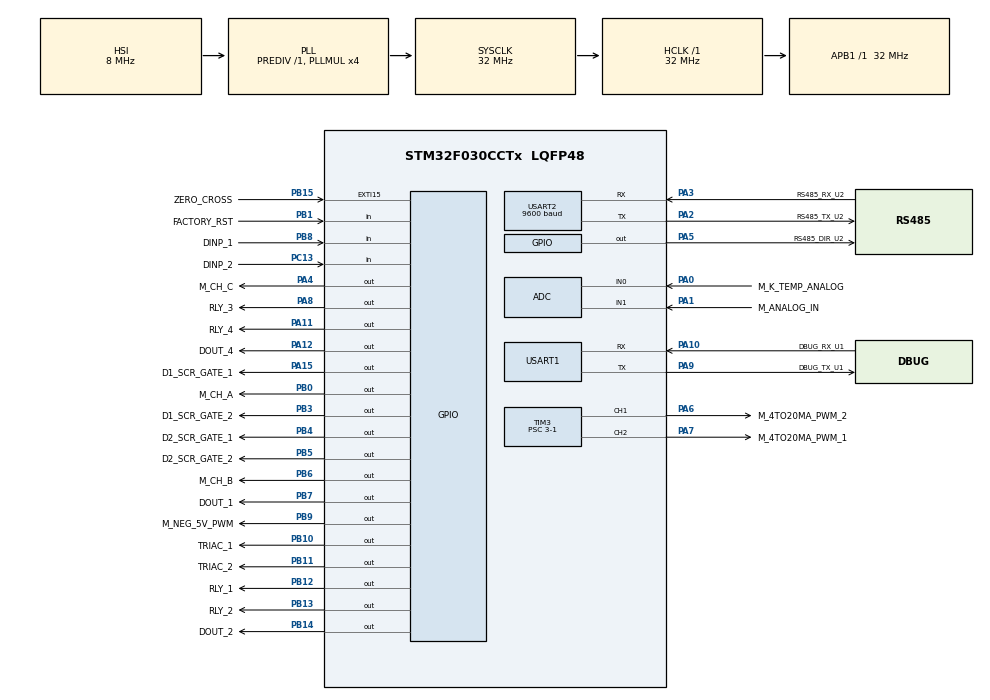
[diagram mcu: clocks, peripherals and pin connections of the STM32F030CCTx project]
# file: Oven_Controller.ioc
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ADC.ContinuousConvMode=DISABLE
ADC.DMAContinuousRequests=DISABLE
ADC.DiscontinuousConvMode=DISABLE
ADC.EOCSelection=ADC_EOC_SINGLE_CONV
ADC.SamplingTime=ADC_SAMPLETIME_71CYCLES_5
IWDG.Prescaler=IWDG_PRESCALER_64
Mcu.Family=STM32F0
Mcu.Name=STM32F030CCTx
Mcu.Package=LQFP48
NVIC.EXTI4_15_IRQn=true\:1\:0\:true\:false\:true\:true\:true
NVIC.TIM14_IRQn=true\:2\:0\:true\:false\:true\:true\:true
NVIC.TIM15_IRQn=true\:2\:0\:true\:false\:true\:true\:true
NVIC.TIM6_IRQn=true\:0\:0\:true\:false\:true\:true\:true
NVIC.TIM7_IRQn=true\:0\:0\:true\:false\:true\:true\:true
NVIC.USART1_IRQn=true\:3\:0\:true\:false\:true\:true\:true
NVIC.USART2_IRQn=true\:0\:0\:true\:false\:true\:true\:true
PA0.GPIO_Label=M_K_TEMP_ANALOG
PA0.Mode=IN0
PA0.Signal=ADC_IN0
PA1.GPIO_Label=M_ANALOG_IN
PA1.Mode=IN1
PA1.Signal=ADC_IN1
PA10.GPIO_Label=DBUG_RX_U1
PA10.Mode=Asynchronous
PA10.Signal=USART1_RX
PA11.GPIO_Label=RLY_4
PA11.GPIO_Speed=GPIO_SPEED_FREQ_HIGH
PA11.Signal=GPIO_Output
PA12.GPIO_Label=DOUT_4
PA12.GPIO_ModeDefaultOutputPP=GPIO_MODE_OUTPUT_OD
PA12.GPIO_PuPd=GPIO_NOPULL
PA12.GPIO_Speed=GPIO_SPEED_FREQ_HIGH
PA12.PinState=GPIO_PIN_SET
PA12.Signal=GPIO_Output
PA15.GPIO_Label=D1_SCR_GATE_1
PA15.Signal=GPIO_Output
PA2.GPIO_Label=RS485_TX_U2
PA2.Mode=Asynchronous
PA2.Signal=USART2_TX
PA3.GPIO_Label=RS485_RX_U2
PA3.Mode=Asynchronous
PA3.Signal=USART2_RX
PA4.GPIO_Label=M_CH_C
PA4.GPIO_Speed=GPIO_SPEED_FREQ_HIGH
PA4.Signal=GPIO_Output
PA5.GPIO_Label=RS485_DIR_U2
PA5.Signal=GPIO_Output
PA6.GPIO_Label=M_4TO20MA_PWM_2
PA6.Signal=S_TIM3_CH1
PA7.GPIO_Label=M_4TO20MA_PWM_1
PA7.Signal=S_TIM3_CH2
PA8.GPIO_Label=RLY_3
PA8.GPIO_Speed=GPIO_SPEED_FREQ_HIGH
PA8.Signal=GPIO_Output
PA9.GPIO_Label=DBUG_TX_U1
PA9.Mode=Asynchronous
PA9.Signal=USART1_TX
PB0.GPIO_Label=M_CH_A
PB0.GPIO_Speed=GPIO_SPEED_FREQ_HIGH
PB0.Signal=GPIO_Output
PB1.GPIO_Label=FACTORY_RST
PB1.Signal=GPIO_Input
PB10.GPIO_Label=TRIAC_1
PB10.Signal=GPIO_Output
PB11.GPIO_Label=TRIAC_2
PB11.Signal=GPIO_Output
PB12.GPIO_Label=RLY_1
PB12.Signal=GPIO_Output
PB13.GPIO_Label=RLY_2
PB13.Signal=GPIO_Output
PB14.GPIO_Label=DOUT_2
PB14.GPIO_ModeDefaultOutputPP=GPIO_MODE_OUTPUT_OD
PB14.GPIO_PuPd=GPIO_NOPULL
PB14.GPIO_Speed=GPIO_SPEED_FREQ_HIGH
PB14.PinState=GPIO_PIN_SET
PB14.Signal=GPIO_Output
PB15.GPIO_Label=ZERO_CROSS
PB15.GPIO_ModeDefaultEXTI=GPIO_MODE_IT_RISING
PB15.Signal=GPXTI15
PB3.GPIO_Label=D1_SCR_GATE_2
PB3.Signal=GPIO_Output
PB4.GPIO_Label=D2_SCR_GATE_1
PB4.Signal=GPIO_Output
PB5.GPIO_Label=D2_SCR_GATE_2
PB5.Signal=GPIO_Output
PB6.GPIO_FM6=SYSCFG_CFGR1_I2C_FMP_PB6
PB6.GPIO_Label=M_CH_B
PB6.GPIO_Speed=GPIO_SPEED_FREQ_HIGH
PB6.Signal=GPIO_Output
PB7.GPIO_FM7=__NULL
PB7.GPIO_Label=DOUT_1
PB7.GPIO_ModeDefaultOutputPP=GPIO_MODE_OUTPUT_OD
PB7.GPIO_PuPd=GPIO_NOPULL
PB7.GPIO_Speed=GPIO_SPEED_FREQ_HIGH
PB7.PinState=GPIO_PIN_SET
PB7.Signal=GPIO_Output
PB8.GPIO_Label=DINP_1
PB8.Signal=GPIO_Input
PB9.GPIO_FM9=SYSCFG_CFGR1_I2C_FMP_PB9
PB9.GPIO_Label=M_NEG_5V_PWM
PB9.GPIO_Speed=GPIO_SPEED_FREQ_HIGH
PB9.Signal=GPIO_Output
PC13.GPIO_Label=DINP_2
PC13.Signal=GPIO_Input
PC14OSC32_IN.GPIO_Label=DINP_3
PC14OSC32_IN.Signal=GPIO_Input
PC15OSC32_OUT.GPIO_Label=DINP_4
PC15OSC32_OUT.Signal=GPIO_Input
ProjectManager.HeapSize=0x200
ProjectManager.StackSize=0x400
ProjectManager.TargetToolchain=STM32CubeIDE
RCC.AHBFreq_Value=32000000
RCC.APB1Freq_Value=32000000
RCC.APB1TimFreq_Value=32000000
RCC.HCLKFreq_Value=32000000
RCC.PLLMUL=RCC_PLL_MUL4
RCC.SYSCLKFreq_VALUE=32000000
RCC.SYSCLKSource=RCC_SYSCLKSOURCE_PLLCLK
SH.S_TIM3_CH1.0=TIM3_CH1,PWM Generation1 CH1
SH.S_TIM3_CH2.0=TIM3_CH2,PWM Generation2 CH2
TIM14.Period=100
TIM14.Prescaler=32-1
TIM15.Period=30000
TIM15.Prescaler=32-1
TIM15.TIM_MasterOutputTrigger=TIM_TRGO_ENABLE
TIM3.Channel-PWM\ Generation1\ CH1=TIM_CHANNEL_1
TIM3.Channel-PWM\ Generation2\ CH2=TIM_CHANNEL_2
TIM3.OCPolarity_1=TIM_OCPOLARITY_HIGH
TIM3.Period=1536-1
TIM3.Prescaler=3-1
TIM3.Pulse-PWM\ Generation1\ CH1=0
TIM3.TIM_MasterOutputTrigger=TIM_TRGO_ENABLE
TIM6.Period=1563
TIM6.Prescaler=32-1
TIM7.Period=3647
TIM7.Prescaler=32-1
USART1.VirtualMode-Asynchronous=VM_ASYNC
USART2.BaudRate=9600
USART2.Parity=PARITY_EVEN
USART2.VirtualMode-Asynchronous=VM_ASYNC
USART2.WordLength=WORDLENGTH_9B
VP_IWDG_VS_IWDG.Mode=IWDG_Activate
VP_TIM14_VS_ClockSourceINT.Mode=Enable_Timer
VP_TIM15_VS_ClockSourceINT.Mode=Internal
VP_TIM3_VS_ClockSourceINT.Mode=Internal
VP_TIM6_VS_ClockSourceINT.Mode=Enable_Timer
VP_TIM7_VS_ClockSourceINT.Mode=Enable_Timer
board=custom

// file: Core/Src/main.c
/* USER CODE BEGIN Header */
/**
  ******************************************************************************
  * @file           : main.c
  * @brief          : Main program body
  ******************************************************************************
  * @attention
  *
  * Copyright (c) 2024 STMicroelectronics.
  * All rights reserved.
  *
  * This software is licensed under terms that can be found in the LICENSE file
  * in the root directory of this software component.
  * If no LICENSE file comes with this software, it is provided AS-IS.
  *
  ******************************************************************************
  */
/* USER CODE END Header */
#include "main.h"

/* USER CODE BEGIN Includes */
#include "OD_PWM.h"
#include "Test.h"
#include "debug.h"

/* USER CODE END Includes */

/* USER CODE BEGIN PM */
// extern uint16_t buf1[500], buf2[500], index, c1, c2;
/* USER CODE END PM */

ADC_HandleTypeDef hadc;

IWDG_HandleTypeDef hiwdg;

TIM_HandleTypeDef htim3;
TIM_HandleTypeDef htim6;
TIM_HandleTypeDef htim7;
TIM_HandleTypeDef htim14;
TIM_HandleTypeDef htim15;

UART_HandleTypeDef huart1;
UART_HandleTypeDef huart2;

/* USER CODE BEGIN PV */

GVar_ts gVar;

/* USER CODE END PV */

void SystemClock_Config(void);
static void MX_GPIO_Init(void);
static void MX_ADC_Init(void);
static void MX_TIM6_Init(void);
static void MX_TIM7_Init(void);
static void MX_USART1_UART_Init(void);
static void MX_USART2_UART_Init(void);
static void MX_TIM3_Init(void);
static void MX_TIM14_Init(void);
static void MX_IWDG_Init(void);
static void MX_TIM15_Init(void);
/* USER CODE BEGIN PFP */
//void DebugPrintf(const char *fmt, ...);
/* USER CODE END PFP */

int main(void)
{

  /* MCU Configuration--------------------------------------------------------*/

  /* Reset of all peripherals, Initializes the Flash interface and the Systick. */
  HAL_Init();

  /* Configure the system clock */
  SystemClock_Config();

  /* Initialize all configured peripherals */
  MX_GPIO_Init();
  MX_ADC_Init();
  MX_TIM6_Init();
  MX_TIM7_Init();
  MX_USART1_UART_Init();
  MX_USART2_UART_Init();
  MX_TIM3_Init();
  MX_TIM14_Init();
  // MX_IWDG_Init();
  MX_TIM15_Init();
  /* USER CODE BEGIN 2 */

//  ExecutionTimeCalculate();
  Test_Init();
  /* USER CODE END 2 */

  /* Infinite loop */
  /* USER CODE BEGIN WHILE */

  while (1)
  {
//	  HAL_UART_Transmit(&huart1, (uint8_t *)msg, strlen(msg), HAL_MAX_DELAY);

	  Test_Handler();

    /* USER CODE END WHILE */

  }
}

void SystemClock_Config(void)
{
  RCC_OscInitTypeDef RCC_OscInitStruct = {0};
  RCC_ClkInitTypeDef RCC_ClkInitStruct = {0};
  RCC_PeriphCLKInitTypeDef PeriphClkInit = {0};

  /** Initializes the RCC Oscillators according to the specified parameters
  * in the RCC_OscInitTypeDef structure.
  */
  RCC_OscInitStruct.OscillatorType = RCC_OSCILLATORTYPE_HSI|RCC_OSCILLATORTYPE_HSI14
                              |RCC_OSCILLATORTYPE_LSI;
  RCC_OscInitStruct.HSIState = RCC_HSI_ON;
  RCC_OscInitStruct.HSI14State = RCC_HSI14_ON;
  RCC_OscInitStruct.HSICalibrationValue = RCC_HSICALIBRATION_DEFAULT;
  RCC_OscInitStruct.HSI14CalibrationValue = 16;
  RCC_OscInitStruct.LSIState = RCC_LSI_ON;
  RCC_OscInitStruct.PLL.PLLState = RCC_PLL_ON;
  RCC_OscInitStruct.PLL.PLLSource = RCC_PLLSOURCE_HSI;
  RCC_OscInitStruct.PLL.PLLMUL = RCC_PLL_MUL4;
  RCC_OscInitStruct.PLL.PREDIV = RCC_PREDIV_DIV1;
  if (HAL_RCC_OscConfig(&RCC_OscInitStruct) != HAL_OK)
  {
    Error_Handler();
  }
  /** Initializes the CPU, AHB and APB buses clocks
  */
  RCC_ClkInitStruct.ClockType = RCC_CLOCKTYPE_HCLK|RCC_CLOCKTYPE_SYSCLK
                              |RCC_CLOCKTYPE_PCLK1;
  RCC_ClkInitStruct.SYSCLKSource = RCC_SYSCLKSOURCE_PLLCLK;
  RCC_ClkInitStruct.AHBCLKDivider = RCC_SYSCLK_DIV1;
  RCC_ClkInitStruct.APB1CLKDivider = RCC_HCLK_DIV1;

  if (HAL_RCC_ClockConfig(&RCC_ClkInitStruct, FLASH_LATENCY_1) != HAL_OK)
  {
    Error_Handler();
  }
  PeriphClkInit.PeriphClockSelection = RCC_PERIPHCLK_USART1;
  PeriphClkInit.Usart1ClockSelection = RCC_USART1CLKSOURCE_PCLK1;
  if (HAL_RCCEx_PeriphCLKConfig(&PeriphClkInit) != HAL_OK)
  {
    Error_Handler();
  }
}

static void MX_ADC_Init(void)
{

  ADC_ChannelConfTypeDef sConfig = {0};

  /** Configure the global features of the ADC (Clock, Resolution, Data Alignment and number of conversion)
  */
  hadc.Instance = ADC1;
  hadc.Init.ClockPrescaler = ADC_CLOCK_ASYNC_DIV1;
  hadc.Init.Resolution = ADC_RESOLUTION_12B;
  hadc.Init.DataAlign = ADC_DATAALIGN_RIGHT;
  hadc.Init.ScanConvMode = ADC_SCAN_DIRECTION_FORWARD;
  hadc.Init.EOCSelection = ADC_EOC_SINGLE_CONV;
  hadc.Init.LowPowerAutoWait = DISABLE;
  hadc.Init.LowPowerAutoPowerOff = DISABLE;
  hadc.Init.ContinuousConvMode = DISABLE;
  hadc.Init.DiscontinuousConvMode = DISABLE;
  hadc.Init.ExternalTrigConv = ADC_SOFTWARE_START;
  hadc.Init.ExternalTrigConvEdge = ADC_EXTERNALTRIGCONVEDGE_NONE;
  hadc.Init.DMAContinuousRequests = DISABLE;
  hadc.Init.Overrun = ADC_OVR_DATA_PRESERVED;
  if (HAL_ADC_Init(&hadc) != HAL_OK)
  {
    Error_Handler();
  }
  /** Configure for the selected ADC regular channel to be converted.
  */
  sConfig.Channel = ADC_CHANNEL_0;
  sConfig.Rank = ADC_RANK_CHANNEL_NUMBER;
  sConfig.SamplingTime = ADC_SAMPLETIME_71CYCLES_5;
  if (HAL_ADC_ConfigChannel(&hadc, &sConfig) != HAL_OK)
  {
    Error_Handler();
  }
  /** Configure for the selected ADC regular channel to be converted.
  */
  sConfig.Channel = ADC_CHANNEL_1;
  if (HAL_ADC_ConfigChannel(&hadc, &sConfig) != HAL_OK)
  {
    Error_Handler();
  }

}

static void MX_IWDG_Init(void)
{

  hiwdg.Instance = IWDG;
  hiwdg.Init.Prescaler = IWDG_PRESCALER_64;
  hiwdg.Init.Window = 4095;
  hiwdg.Init.Reload = 4095;
  if (HAL_IWDG_Init(&hiwdg) != HAL_OK)
  {
    Error_Handler();
  }

}

static void MX_TIM3_Init(void)
{

  TIM_ClockConfigTypeDef sClockSourceConfig = {0};
  TIM_MasterConfigTypeDef sMasterConfig = {0};
  TIM_OC_InitTypeDef sConfigOC = {0};

  htim3.Instance = TIM3;
  htim3.Init.Prescaler = 3-1;
  htim3.Init.CounterMode = TIM_COUNTERMODE_UP;
  htim3.Init.Period = 1536-1;
  htim3.Init.ClockDivision = TIM_CLOCKDIVISION_DIV1;
  htim3.Init.AutoReloadPreload = TIM_AUTORELOAD_PRELOAD_DISABLE;
  if (HAL_TIM_Base_Init(&htim3) != HAL_OK)
  {
    Error_Handler();
  }
  sClockSourceConfig.ClockSource = TIM_CLOCKSOURCE_INTERNAL;
  if (HAL_TIM_ConfigClockSource(&htim3, &sClockSourceConfig) != HAL_OK)
  {
    Error_Handler();
  }
  if (HAL_TIM_PWM_Init(&htim3) != HAL_OK)
  {
    Error_Handler();
  }
  sMasterConfig.MasterOutputTrigger = TIM_TRGO_ENABLE;
  sMasterConfig.MasterSlaveMode = TIM_MASTERSLAVEMODE_DISABLE;
  if (HAL_TIMEx_MasterConfigSynchronization(&htim3, &sMasterConfig) != HAL_OK)
  {
    Error_Handler();
  }
  sConfigOC.OCMode = TIM_OCMODE_PWM1;
  sConfigOC.Pulse = 0;
  sConfigOC.OCPolarity = TIM_OCPOLARITY_HIGH;
  sConfigOC.OCFastMode = TIM_OCFAST_DISABLE;
  if (HAL_TIM_PWM_ConfigChannel(&htim3, &sConfigOC, TIM_CHANNEL_1) != HAL_OK)
  {
    Error_Handler();
  }
  if (HAL_TIM_PWM_ConfigChannel(&htim3, &sConfigOC, TIM_CHANNEL_2) != HAL_OK)
  {
    Error_Handler();
  }
  HAL_TIM_MspPostInit(&htim3);

}

static void MX_TIM6_Init(void)
{

  htim6.Instance = TIM6;
  htim6.Init.Prescaler = 32-1;
  htim6.Init.CounterMode = TIM_COUNTERMODE_UP;
  htim6.Init.Period = 1563;
  htim6.Init.AutoReloadPreload = TIM_AUTORELOAD_PRELOAD_DISABLE;
  if (HAL_TIM_Base_Init(&htim6) != HAL_OK)
  {
    Error_Handler();
  }

}

static void MX_TIM7_Init(void)
{

  htim7.Instance = TIM7;
  htim7.Init.Prescaler = 32-1;
  htim7.Init.CounterMode = TIM_COUNTERMODE_UP;
  htim7.Init.Period = 3647;
  htim7.Init.AutoReloadPreload = TIM_AUTORELOAD_PRELOAD_DISABLE;
  if (HAL_TIM_Base_Init(&htim7) != HAL_OK)
  {
    Error_Handler();
  }

}

static void MX_TIM14_Init(void)
{

  htim14.Instance = TIM14;
  htim14.Init.Prescaler = 32-1;
  htim14.Init.CounterMode = TIM_COUNTERMODE_UP;
  htim14.Init.Period = 100;
  htim14.Init.ClockDivision = TIM_CLOCKDIVISION_DIV1;
  htim14.Init.AutoReloadPreload = TIM_AUTORELOAD_PRELOAD_DISABLE;
  if (HAL_TIM_Base_Init(&htim14) != HAL_OK)
  {
    Error_Handler();
  }

}

static void MX_TIM15_Init(void)
{

  TIM_ClockConfigTypeDef sClockSourceConfig = {0};
  TIM_MasterConfigTypeDef sMasterConfig = {0};

  htim15.Instance = TIM15;
  htim15.Init.Prescaler = 32-1;
  htim15.Init.CounterMode = TIM_COUNTERMODE_UP;
  htim15.Init.Period = 30000;
  htim15.Init.ClockDivision = TIM_CLOCKDIVISION_DIV1;
  htim15.Init.RepetitionCounter = 0;
  htim15.Init.AutoReloadPreload = TIM_AUTORELOAD_PRELOAD_DISABLE;
  if (HAL_TIM_Base_Init(&htim15) != HAL_OK)
  {
    Error_Handler();
  }
  sClockSourceConfig.ClockSource = TIM_CLOCKSOURCE_INTERNAL;
  if (HAL_TIM_ConfigClockSource(&htim15, &sClockSourceConfig) != HAL_OK)
  {
    Error_Handler();
  }
  sMasterConfig.MasterOutputTrigger = TIM_TRGO_ENABLE;
  sMasterConfig.MasterSlaveMode = TIM_MASTERSLAVEMODE_DISABLE;
  if (HAL_TIMEx_MasterConfigSynchronization(&htim15, &sMasterConfig) != HAL_OK)
  {
    Error_Handler();
  }

}

static void MX_USART1_UART_Init(void)
{

  huart1.Instance = USART1;
  huart1.Init.BaudRate = 115200;
  huart1.Init.WordLength = UART_WORDLENGTH_8B;
  huart1.Init.StopBits = UART_STOPBITS_1;
  huart1.Init.Parity = UART_PARITY_NONE;
  huart1.Init.Mode = UART_MODE_TX_RX;
  huart1.Init.HwFlowCtl = UART_HWCONTROL_NONE;
  huart1.Init.OverSampling = UART_OVERSAMPLING_16;
  huart1.Init.OneBitSampling = UART_ONE_BIT_SAMPLE_DISABLE;
  huart1.AdvancedInit.AdvFeatureInit = UART_ADVFEATURE_NO_INIT;
  if (HAL_UART_Init(&huart1) != HAL_OK)
  {
    Error_Handler();
  }

}

static void MX_USART2_UART_Init(void)
{

  huart2.Instance = USART2;
  huart2.Init.BaudRate = 9600;
  huart2.Init.WordLength = UART_WORDLENGTH_9B;
  huart2.Init.StopBits = UART_STOPBITS_1;
  huart2.Init.Parity = UART_PARITY_EVEN;
  huart2.Init.Mode = UART_MODE_TX_RX;
  huart2.Init.HwFlowCtl = UART_HWCONTROL_NONE;
  huart2.Init.OverSampling = UART_OVERSAMPLING_16;
  huart2.Init.OneBitSampling = UART_ONE_BIT_SAMPLE_DISABLE;
  huart2.AdvancedInit.AdvFeatureInit = UART_ADVFEATURE_NO_INIT;
  if (HAL_UART_Init(&huart2) != HAL_OK)
  {
    Error_Handler();
  }

}

static void MX_GPIO_Init(void)
{
  GPIO_InitTypeDef GPIO_InitStruct = {0};

  /* GPIO Ports Clock Enable */
  __HAL_RCC_GPIOC_CLK_ENABLE();
  __HAL_RCC_GPIOA_CLK_ENABLE();
  __HAL_RCC_GPIOB_CLK_ENABLE();

  /*Configure GPIO pin Output Level */
  HAL_GPIO_WritePin(GPIOA, M_CH_C_Pin|RS485_DIR_U2_Pin|RLY_3_Pin|RLY_4_Pin
                          |D1_SCR_GATE_1_Pin, GPIO_PIN_RESET);

  /*Configure GPIO pin Output Level */
  HAL_GPIO_WritePin(GPIOB, M_CH_A_Pin|TRIAC_1_Pin|TRIAC_2_Pin|RLY_1_Pin
                          |RLY_2_Pin|D1_SCR_GATE_2_Pin|D2_SCR_GATE_1_Pin|D2_SCR_GATE_2_Pin
                          |M_CH_B_Pin|M_NEG_5V_PWM_Pin, GPIO_PIN_RESET);

  /*Configure GPIO pin Output Level */
  HAL_GPIO_WritePin(GPIOB, DOUT_2_Pin|DOUT_1_Pin, GPIO_PIN_SET);

  /*Configure GPIO pin Output Level */
  HAL_GPIO_WritePin(DOUT_4_GPIO_Port, DOUT_4_Pin, GPIO_PIN_SET);

  /*Configure GPIO pins : DINP_2_Pin DINP_3_Pin DINP_4_Pin */
  GPIO_InitStruct.Pin = DINP_2_Pin|DINP_3_Pin|DINP_4_Pin;
  GPIO_InitStruct.Mode = GPIO_MODE_INPUT;
  GPIO_InitStruct.Pull = GPIO_NOPULL;
  HAL_GPIO_Init(GPIOC, &GPIO_InitStruct);

  /*Configure GPIO pins : M_CH_C_Pin RLY_3_Pin RLY_4_Pin */
  GPIO_InitStruct.Pin = M_CH_C_Pin|RLY_3_Pin|RLY_4_Pin;
  GPIO_InitStruct.Mode = GPIO_MODE_OUTPUT_PP;
  GPIO_InitStruct.Pull = GPIO_NOPULL;
  GPIO_InitStruct.Speed = GPIO_SPEED_FREQ_HIGH;
  HAL_GPIO_Init(GPIOA, &GPIO_InitStruct);

  /*Configure GPIO pins : RS485_DIR_U2_Pin D1_SCR_GATE_1_Pin */
  GPIO_InitStruct.Pin = RS485_DIR_U2_Pin|D1_SCR_GATE_1_Pin;
  GPIO_InitStruct.Mode = GPIO_MODE_OUTPUT_PP;
  GPIO_InitStruct.Pull = GPIO_NOPULL;
  GPIO_InitStruct.Speed = GPIO_SPEED_FREQ_LOW;
  HAL_GPIO_Init(GPIOA, &GPIO_InitStruct);

  /*Configure GPIO pins : M_CH_A_Pin M_CH_B_Pin M_NEG_5V_PWM_Pin */
  GPIO_InitStruct.Pin = M_CH_A_Pin|M_CH_B_Pin|M_NEG_5V_PWM_Pin;
  GPIO_InitStruct.Mode = GPIO_MODE_OUTPUT_PP;
  GPIO_InitStruct.Pull = GPIO_NOPULL;
  GPIO_InitStruct.Speed = GPIO_SPEED_FREQ_HIGH;
  HAL_GPIO_Init(GPIOB, &GPIO_InitStruct);

  /*Configure GPIO pins : FACTORY_RST_Pin DINP_1_Pin */
  GPIO_InitStruct.Pin = FACTORY_RST_Pin|DINP_1_Pin;
  GPIO_InitStruct.Mode = GPIO_MODE_INPUT;
  GPIO_InitStruct.Pull = GPIO_NOPULL;
  HAL_GPIO_Init(GPIOB, &GPIO_InitStruct);

  /*Configure GPIO pins : TRIAC_1_Pin TRIAC_2_Pin RLY_1_Pin RLY_2_Pin
                           D1_SCR_GATE_2_Pin D2_SCR_GATE_1_Pin D2_SCR_GATE_2_Pin */
  GPIO_InitStruct.Pin = TRIAC_1_Pin|TRIAC_2_Pin|RLY_1_Pin|RLY_2_Pin
                          |D1_SCR_GATE_2_Pin|D2_SCR_GATE_1_Pin|D2_SCR_GATE_2_Pin;
  GPIO_InitStruct.Mode = GPIO_MODE_OUTPUT_PP;
  GPIO_InitStruct.Pull = GPIO_NOPULL;
  GPIO_InitStruct.Speed = GPIO_SPEED_FREQ_LOW;
  HAL_GPIO_Init(GPIOB, &GPIO_InitStruct);

  /*Configure GPIO pins : DOUT_2_Pin DOUT_1_Pin */
  GPIO_InitStruct.Pin = DOUT_2_Pin|DOUT_1_Pin;
  GPIO_InitStruct.Mode = GPIO_MODE_OUTPUT_OD;
  GPIO_InitStruct.Pull = GPIO_NOPULL;
  GPIO_InitStruct.Speed = GPIO_SPEED_FREQ_HIGH;
  HAL_GPIO_Init(GPIOB, &GPIO_InitStruct);

  /*Configure GPIO pin : ZERO_CROSS_Pin */
  GPIO_InitStruct.Pin = ZERO_CROSS_Pin;
  GPIO_InitStruct.Mode = GPIO_MODE_IT_RISING;
  GPIO_InitStruct.Pull = GPIO_NOPULL;
  HAL_GPIO_Init(ZERO_CROSS_GPIO_Port, &GPIO_InitStruct);

  /*Configure GPIO pin : DOUT_4_Pin */
  GPIO_InitStruct.Pin = DOUT_4_Pin;
  GPIO_InitStruct.Mode = GPIO_MODE_OUTPUT_OD;
  GPIO_InitStruct.Pull = GPIO_NOPULL;
  GPIO_InitStruct.Speed = GPIO_SPEED_FREQ_HIGH;
  HAL_GPIO_Init(DOUT_4_GPIO_Port, &GPIO_InitStruct);

  /**/
  HAL_I2CEx_EnableFastModePlus(SYSCFG_CFGR1_I2C_FMP_PB6);

  /**/
  HAL_I2CEx_EnableFastModePlus(SYSCFG_CFGR1_I2C_FMP_PB9);

  /* EXTI interrupt init*/
  HAL_NVIC_SetPriority(EXTI4_15_IRQn, 1, 0);
  HAL_NVIC_EnableIRQ(EXTI4_15_IRQn);

}

void Error_Handler(void)
{
  __disable_irq();
  while (1)
  {
  }
}
